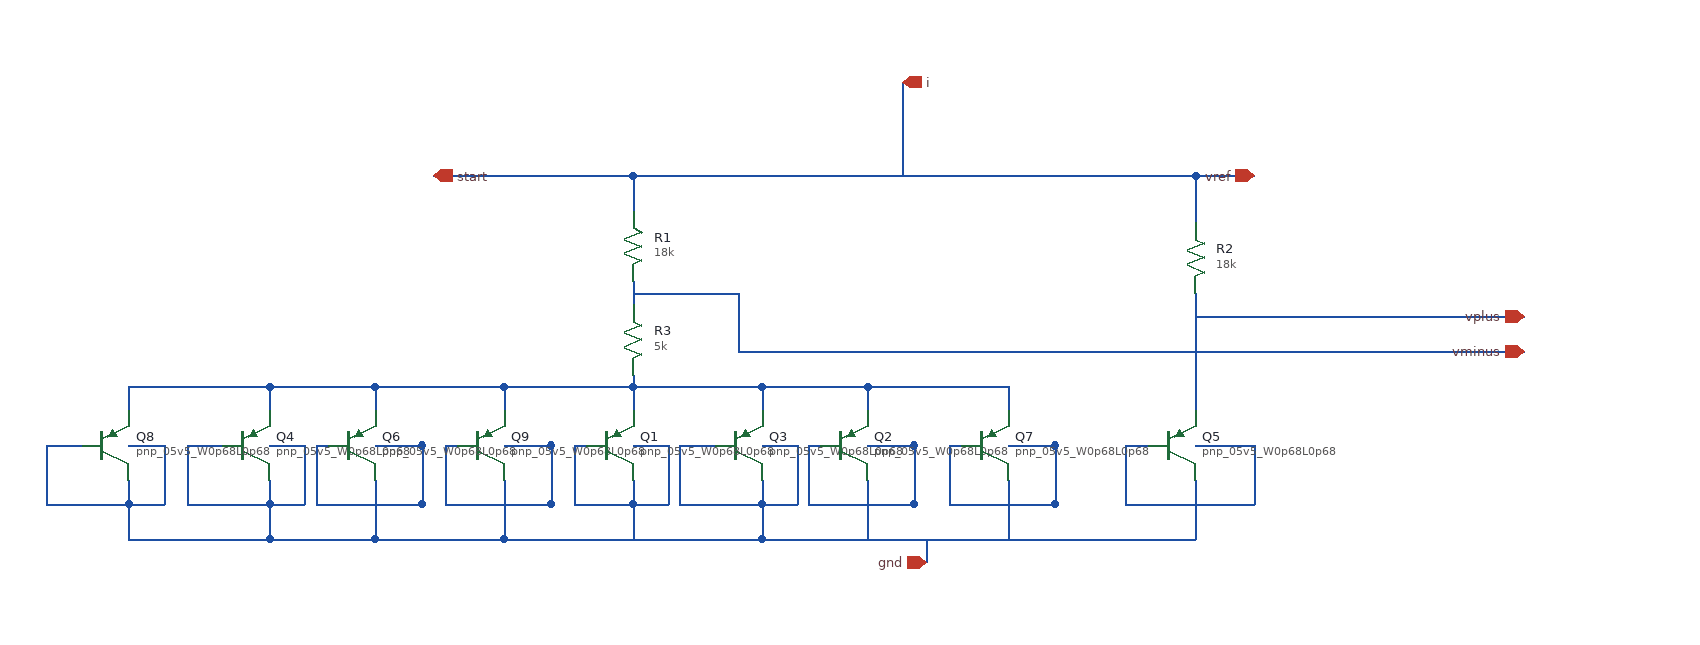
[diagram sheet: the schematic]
v {xschem version=2.9.9 file_version=1.2 }
G {}
K {}
V {}
S {}
E {}
N 1910 -1650 1910 -1630 { lab=vminus}
N 1910 -1740 2200 -1740 { lab=start}
N 2390 -1740 2440 -1740 { lab=vref}
N 1910 -1740 1910 -1730 { lab=start}
N 1910 -1730 1910 -1710 { lab=start}
N 2390 -1640 2390 -1600 { lab=vplus}
N 2390 -1740 2390 -1700 { lab=start}
N 2020 -1510 2050 -1510 { lab=gnd}
N 2050 -1510 2050 -1460 { lab=gnd}
N 2020 -1460 2050 -1460 { lab=gnd}
N 2020 -1480 2020 -1460 { lab=gnd}
N 2020 -1460 2020 -1430 { lab=gnd}
N 2200 -1740 2390 -1740 { lab=start}
N 2390 -1600 2390 -1540 { lab=vplus}
N 2330 -1510 2350 -1510 { lab=gnd}
N 2330 -1510 2330 -1460 { lab=gnd}
N 2330 -1460 2440 -1460 { lab=gnd}
N 2440 -1510 2440 -1460 { lab=gnd}
N 2390 -1510 2440 -1510 { lab=gnd}
N 2390 -1480 2390 -1460 { lab=gnd}
N 2390 -1460 2390 -1430 { lab=gnd}
N 2020 -1560 2020 -1540 { lab=#net1}
N 2390 -1620 2670 -1620 { lab=vplus}
N 2000 -1640 2000 -1590 { lab=vminus}
N 1910 -1640 2000 -1640 { lab=vminus}
N 1750 -1510 1760 -1510 { lab=gnd}
N 1750 -1510 1750 -1460 { lab=gnd}
N 1750 -1460 1840 -1460 { lab=gnd}
N 1840 -1510 1840 -1460 { lab=gnd}
N 1800 -1510 1840 -1510 { lab=gnd}
N 1800 -1480 1800 -1460 { lab=gnd}
N 1800 -1460 1800 -1430 { lab=gnd}
N 1800 -1560 1800 -1540 { lab=#net1}
N 1800 -1560 1910 -1560 { lab=#net1}
N 1950 -1510 1980 -1510 { lab=gnd}
N 1950 -1510 1950 -1460 { lab=gnd}
N 1950 -1460 2020 -1460 { lab=gnd}
N 1800 -1430 2020 -1430 { lab=gnd}
N 1910 -1560 2020 -1560 { lab=#net1}
N 1910 -1570 1910 -1560 { lab=#net1}
N 2020 -1430 2390 -1430 { lab=gnd}
N 2160 -1430 2160 -1410 { lab=gnd}
N 1910 -1510 1940 -1510 { lab=gnd}
N 1940 -1510 1940 -1460 { lab=gnd}
N 1910 -1460 1940 -1460 { lab=gnd}
N 1910 -1480 1910 -1460 { lab=gnd}
N 1910 -1460 1910 -1430 { lab=gnd}
N 1910 -1560 1910 -1540 { lab=#net1}
N 1840 -1510 1840 -1460 { lab=gnd}
N 1860 -1510 1870 -1510 { lab=gnd}
N 1860 -1510 1860 -1460 { lab=gnd}
N 1860 -1460 1910 -1460 { lab=gnd}
N 2060 -1510 2070 -1510 { lab=gnd}
N 2060 -1510 2060 -1460 { lab=gnd}
N 2060 -1460 2150 -1460 { lab=gnd}
N 2150 -1510 2150 -1460 { lab=gnd}
N 2110 -1510 2150 -1510 { lab=gnd}
N 2110 -1480 2110 -1460 { lab=gnd}
N 2110 -1460 2110 -1430 { lab=gnd}
N 2110 -1560 2110 -1540 { lab=#net1}
N 2150 -1510 2150 -1460 { lab=gnd}
N 2020 -1560 2110 -1560 { lab=#net1}
N 1600 -1510 1630 -1510 { lab=gnd}
N 1630 -1510 1630 -1460 { lab=gnd}
N 1600 -1460 1630 -1460 { lab=gnd}
N 1600 -1480 1600 -1460 { lab=gnd}
N 1600 -1460 1600 -1430 { lab=gnd}
N 1600 -1560 1600 -1540 { lab=#net1}
N 1530 -1510 1560 -1510 { lab=gnd}
N 1530 -1510 1530 -1460 { lab=gnd}
N 1530 -1460 1600 -1460 { lab=gnd}
N 1640 -1510 1650 -1510 { lab=gnd}
N 1640 -1510 1640 -1460 { lab=gnd}
N 1640 -1460 1730 -1460 { lab=gnd}
N 1730 -1510 1730 -1460 { lab=gnd}
N 1690 -1510 1730 -1510 { lab=gnd}
N 1690 -1480 1690 -1460 { lab=gnd}
N 1690 -1460 1690 -1430 { lab=gnd}
N 1690 -1560 1690 -1540 { lab=#net1}
N 1730 -1510 1730 -1460 { lab=gnd}
N 1600 -1560 1690 -1560 { lab=#net1}
N 1690 -1430 1800 -1430 { lab=gnd}
N 1600 -1430 1690 -1430 { lab=gnd}
N 2180 -1510 2190 -1510 { lab=gnd}
N 2180 -1510 2180 -1460 { lab=gnd}
N 2180 -1460 2270 -1460 { lab=gnd}
N 2270 -1510 2270 -1460 { lab=gnd}
N 2230 -1510 2270 -1510 { lab=gnd}
N 2230 -1480 2230 -1460 { lab=gnd}
N 2230 -1560 2230 -1540 { lab=#net1}
N 2270 -1510 2270 -1460 { lab=gnd}
N 2230 -1460 2230 -1430 { lab=gnd}
N 2110 -1560 2230 -1560 { lab=#net1}
N 1690 -1560 1800 -1560 { lab=#net1}
N 1480 -1510 1510 -1510 { lab=gnd}
N 1510 -1510 1510 -1460 { lab=gnd}
N 1480 -1460 1510 -1460 { lab=gnd}
N 1480 -1480 1480 -1460 { lab=gnd}
N 1480 -1460 1480 -1430 { lab=gnd}
N 1480 -1560 1480 -1540 { lab=#net1}
N 1410 -1510 1440 -1510 { lab=gnd}
N 1410 -1510 1410 -1460 { lab=gnd}
N 1410 -1460 1480 -1460 { lab=gnd}
N 1480 -1560 1600 -1560 { lab=#net1}
N 1480 -1430 1600 -1430 { lab=gnd}
N 2140 -1820 2140 -1740 { lab=i}
N 1740 -1740 1910 -1740 { lab=start}
N 2000 -1590 2670 -1590 { lab=vminus}
C {sky130_fd_pr/pnp_05v5.sym} 2000 -1510 0 0 {name=Q3
model=pnp_05v5_W0p68L0p68
spiceprefix=X
}
C {sky130_fd_pr/pnp_05v5.sym} 2370 -1510 0 0 {name=Q5
model=pnp_05v5_W0p68L0p68
spiceprefix=X
}
C {sky130_fd_pr/pnp_05v5.sym} 1780 -1510 0 0 {name=Q9
model=pnp_05v5_W0p68L0p68
spiceprefix=X
}
C {sky130_fd_pr/pnp_05v5.sym} 1890 -1510 0 0 {name=Q1
model=pnp_05v5_W0p68L0p68
spiceprefix=X
}
C {sky130_fd_pr/pnp_05v5.sym} 2090 -1510 0 0 {name=Q2
model=pnp_05v5_W0p68L0p68
spiceprefix=X
}
C {sky130_fd_pr/pnp_05v5.sym} 1580 -1510 0 0 {name=Q4
model=pnp_05v5_W0p68L0p68
spiceprefix=X
}
C {sky130_fd_pr/pnp_05v5.sym} 1670 -1510 0 0 {name=Q6
model=pnp_05v5_W0p68L0p68
spiceprefix=X
}
C {sky130_fd_pr/pnp_05v5.sym} 2210 -1510 0 0 {name=Q7
model=pnp_05v5_W0p68L0p68
spiceprefix=X
}
C {sky130_fd_pr/pnp_05v5.sym} 1460 -1510 0 0 {name=Q8
model=pnp_05v5_W0p68L0p68
spiceprefix=X
}
C {devices/iopin.sym} 2160 -1410 0 0 {name=p3 lab=gnd}
C {devices/iopin.sym} 1740 -1740 0 1 {name=p4 lab=start}
C {devices/iopin.sym} 2140 -1820 0 1 {name=p1 lab=i}
C {devices/iopin.sym} 2440 -1740 0 0 {name=p2 lab=vref}
C {devices/iopin.sym} 2670 -1620 0 0 {name=p5 lab=vplus}
C {devices/iopin.sym} 2670 -1590 0 0 {name=p6 lab=vminus}
C {devices/res.sym} 1910 -1680 0 0 {name=R1
value=18k
footprint=1206
device=resistor
m=1}
C {devices/res.sym} 2390 -1670 0 0 {name=R2
value=18k
footprint=1206
device=resistor
m=1}
C {devices/res.sym} 1910 -1600 0 0 {name=R3
value=5k
footprint=1206
device=resistor
m=1}
